VERSION 5.7 ;
  NOWIREEXTENSIONATPIN ON ;
  DIVIDERCHAR "/" ;
  BUSBITCHARS "[]" ;
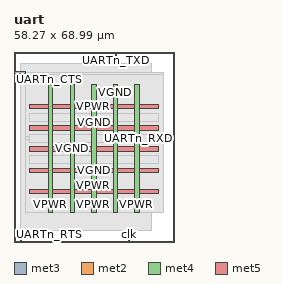
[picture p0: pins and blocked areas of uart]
MACRO uart
  CLASS BLOCK ;
  FOREIGN uart ;
  ORIGIN 0.000 0.000 ;
  SIZE 58.270 BY 68.990 ;
  PIN UARTn_CTS
    DIRECTION INPUT ;
    USE SIGNAL ;
    PORT
      LAYER met3 ;
        RECT 0.000 61.240 4.000 61.840 ;
    END
  END UARTn_CTS
  PIN UARTn_RTS
    DIRECTION OUTPUT TRISTATE ;
    USE SIGNAL ;
    PORT
      LAYER met2 ;
        RECT 2.390 0.000 2.670 4.000 ;
    END
  END UARTn_RTS
  PIN UARTn_RXD
    DIRECTION INPUT ;
    USE SIGNAL ;
    PORT
      LAYER met3 ;
        RECT 54.270 37.440 58.270 38.040 ;
    END
  END UARTn_RXD
  PIN UARTn_TXD
    DIRECTION OUTPUT TRISTATE ;
    USE SIGNAL ;
    PORT
      LAYER met2 ;
        RECT 36.890 64.990 37.170 68.990 ;
    END
  END UARTn_TXD
  PIN clk
    DIRECTION INPUT ;
    USE SIGNAL ;
    PORT
      LAYER met2 ;
        RECT 41.490 0.000 41.770 4.000 ;
    END
  END clk
  PIN VPWR
    DIRECTION INOUT ;
    USE POWER ;
    PORT
      LAYER met4 ;
        RECT 43.820 10.640 45.420 57.360 ;
    END
  END VPWR
  PIN VPWR
    DIRECTION INOUT ;
    USE POWER ;
    PORT
      LAYER met4 ;
        RECT 28.180 10.640 29.780 57.360 ;
    END
  END VPWR
  PIN VPWR
    DIRECTION INOUT ;
    USE POWER ;
    PORT
      LAYER met4 ;
        RECT 12.540 10.640 14.140 57.360 ;
    END
  END VPWR
  PIN VPWR
    DIRECTION INOUT ;
    USE POWER ;
    PORT
      LAYER met5 ;
        RECT 5.520 48.375 52.440 49.975 ;
    END
  END VPWR
  PIN VPWR
    DIRECTION INOUT ;
    USE POWER ;
    PORT
      LAYER met5 ;
        RECT 5.520 32.960 52.440 34.560 ;
    END
  END VPWR
  PIN VPWR
    DIRECTION INOUT ;
    USE POWER ;
    PORT
      LAYER met5 ;
        RECT 5.520 17.545 52.440 19.145 ;
    END
  END VPWR
  PIN VGND
    DIRECTION INOUT ;
    USE GROUND ;
    PORT
      LAYER met4 ;
        RECT 36.000 10.640 37.600 57.360 ;
    END
  END VGND
  PIN VGND
    DIRECTION INOUT ;
    USE GROUND ;
    PORT
      LAYER met4 ;
        RECT 20.360 10.640 21.960 57.360 ;
    END
  END VGND
  PIN VGND
    DIRECTION INOUT ;
    USE GROUND ;
    PORT
      LAYER met5 ;
        RECT 5.520 40.665 52.440 42.265 ;
    END
  END VGND
  PIN VGND
    DIRECTION INOUT ;
    USE GROUND ;
    PORT
      LAYER met5 ;
        RECT 5.520 25.255 52.440 26.855 ;
    END
  END VGND
  OBS
      LAYER li1 ;
        RECT 5.520 10.795 52.440 57.205 ;
      LAYER met1 ;
        RECT 2.370 10.640 52.440 57.360 ;
      LAYER met2 ;
        RECT 2.400 64.710 36.610 64.990 ;
        RECT 37.450 64.710 50.040 64.990 ;
        RECT 2.400 4.280 50.040 64.710 ;
        RECT 2.950 4.000 41.210 4.280 ;
        RECT 42.050 4.000 50.040 4.280 ;
      LAYER met3 ;
        RECT 4.400 60.840 54.270 61.705 ;
        RECT 4.000 38.440 54.270 60.840 ;
        RECT 4.000 37.040 53.870 38.440 ;
        RECT 4.000 10.715 54.270 37.040 ;
      LAYER met5 ;
        RECT 5.520 43.865 52.440 46.775 ;
        RECT 5.520 36.160 52.440 39.065 ;
        RECT 5.520 28.455 52.440 31.360 ;
  END
END uart
END LIBRARY

